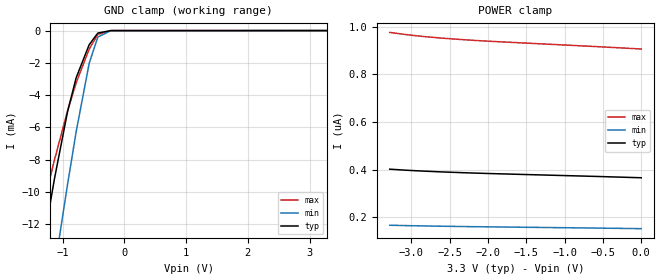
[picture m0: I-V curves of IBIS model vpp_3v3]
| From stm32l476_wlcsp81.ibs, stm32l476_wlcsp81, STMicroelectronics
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|   Model vpp_3v3
[Model]  vpp_3v3
Model_type Input
Polarity   Non-Inverting
Vinl =   0.990000V
Vinh =   2.310000V
C_comp   3.053800pF   3.033900pF   3.062400pF
[Temperature Range]   25.000000   0.140000k   -40.000000
[Pullup Reference]   3.300000V   2.700000V   3.600000V
[Pulldown Reference]   0.0V   0.0V   0.0V
[POWER Clamp Reference]   3.300000V   2.700000V   3.600000V
[GND Clamp Reference]   0.0V   0.0V   0.0V
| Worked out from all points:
|   GND clamp passes 1 mA (typ) near -0.59 V on its own axis
[GND_clamp]
|Voltage   I(typ)   I(min)   I(max)
-3.3V     -61.09mA   -72.79mA   -52.83mA
-1.55V    -18.59mA   -25.57mA   -15.07mA
-1.48V    -16.97mA   -23.74mA   -13.74mA
-1.41V    -15.37mA   -21.92mA   -12.47mA
-1.34V    -13.78mA   -20.1mA    -11.27mA
-1.13V    -9.15mA    -14.74mA   -7.996mA
-920mV    -5.027mA   -9.541mA   -4.973mA
-780mV    -2.919mA   -6.261mA   -3.233mA
-570mV    -877.4uA   -2.033mA   -1.151mA
-430mV    -153.6uA   -402.9uA   -228.9uA
-220mV    -650nA     -5.548uA   -411.2nA
3.28V     365.7nA    152.1nA    899.8nA
[POWER_clamp]
|Voltage   I(typ)   I(min)   I(max)
-3.28V    401.9nA    166.8nA    975.6nA
-3.08V    397.8nA    165.3nA    966.9nA
-2.96V    395.7nA    164.6nA    962.4nA
-2.84V    393.8nA    163.9nA    958.4nA
-2.6V     390.4nA    162.6nA    951.5nA
-2.32V    387.1nA    161.3nA    945nA
-2.12V    385nA      160.5nA    941nA
-1.88V    382.7nA    159.6nA    936.8nA
-600mV    371.6nA    154.9nA    916.3nA
0V        365.9nA    152.4nA    906nA
